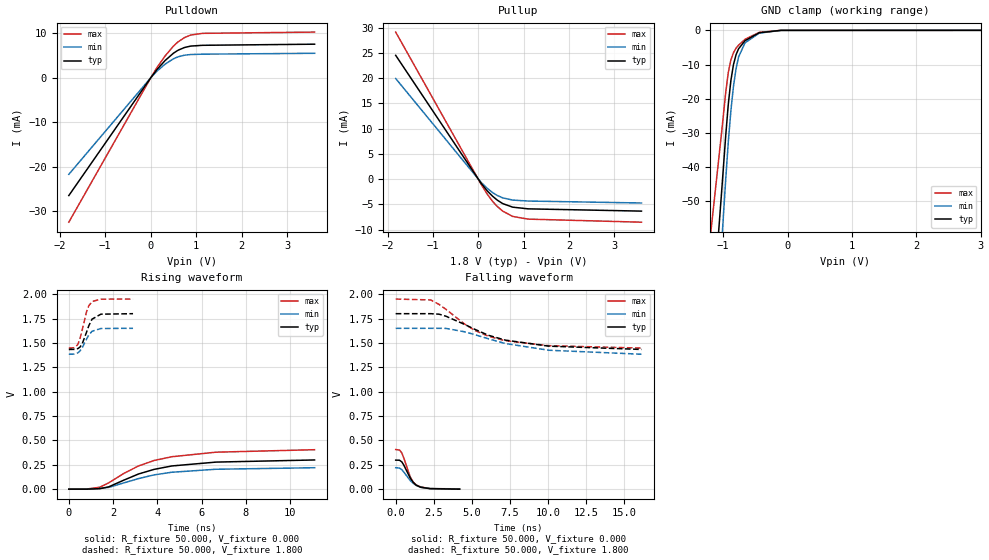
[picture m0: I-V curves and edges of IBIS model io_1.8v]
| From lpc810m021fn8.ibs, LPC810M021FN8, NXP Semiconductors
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[Model]   io_1.8v
Model_type I/O
Vinl=5.600E-01
Vinh=1.260E+00
Vref=0.000E+00
Rref=1.000E+06
Cref=2.000E-11
Vmeas=9.000E-01
C_comp   6.740E-13   6.620E-13   6.860E-13
[Voltage Range]   1.800E+00   1.650E+00   1.950E+00
[POWER Clamp Reference]   1.800E+00   1.650E+00   1.950E+00
[GND Clamp Reference]   0.000E+00   0.000E+00   0.000E+00
[Pullup Reference]   1.800E+00   1.650E+00   1.950E+00
[Pulldown Reference]   0.000E+00   0.000E+00   0.000E+00
[Temperature Range]   25   85   -40
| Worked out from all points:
|   slope of the pulldown table from 0 to 0.27 V, typ, clamps not added: 80.1 ohm
|   slope of the pullup table from 0 to 0.27 V, typ, clamps not added: 90.2 ohm
|   GND clamp passes 1 mA (typ) near -0.48 V on its own axis
|   rising waveform, R_fixture 50.000, V_fixture 0.000: 20-80 % time 2.52ns typ, 2.55ns min, 2.51ns max; typ from 0 V to 0.3 V
|   falling waveform, R_fixture 50.000, V_fixture 0.000: 20-80 % time 651ps typ, 759ps min, 578ps max; typ from 0.298 V to 0 V
|   rising waveform, R_fixture 50.000, V_fixture 1.800: 20-80 % time 362ps typ, 383ps min, 333ps max; typ from 1.43 V to 1.8 V
|   falling waveform, R_fixture 50.000, V_fixture 1.800: 20-80 % time 3.86ns typ, 4.4ns min, 3.27ns max; typ from 1.8 V to 1.43 V
[GND Clamp]
-1.8V     -242.4mA   -287.8mA   -165mA
-1.02V    -46.29mA   -61.32mA   -29.16mA
-960mV    -30.77mA   -43.57mA   -18.16mA
-920mV    -21.6mA    -32.63mA   -12.29mA
-880mV    -14.71mA   -23.53mA   -8.671mA
-840mV    -10.06mA   -16.42mA   -6.556mA
-800mV    -7.156mA   -11.27mA   -5.232mA
-760mV    -5.384mA   -7.778mA   -4.336mA
-660mV    -3.035mA   -3.64mA    -2.632mA
-440mV    -704.5uA   -820uA     -592.1uA
-100mV    -9.589uA   -9.536uA   -9.136uA
3.6V      0A         0A         0A
[POWER Clamp]
-1.8V     0A         0A         0A
3.6V      0A         0A         0A
[Pullup]
-1.82V    24.51mA    19.92mA    29.11mA
60mV      -766.2uA   -617.8uA   -963.6uA
200mV     -2.341mA   -1.823mA   -2.986mA
320mV     -3.405mA   -2.678mA   -4.431mA
420mV     -4.154mA   -3.232mA   -5.407mA
540mV     -4.841mA   -3.705mA   -6.323mA
760mV     -5.544mA   -4.145mA   -7.381mA
1.1V      -5.879mA   -4.334mA   -7.913mA
3.6V      -6.329mA   -4.721mA   -8.521mA
[Pulldown]
-1.8V     -26.43mA   -21.67mA   -32.41mA
0V        0A         0A         0A
140mV     1.894mA    1.523mA    2.358mA
320mV     3.92mA     3.098mA    4.957mA
500mV     5.527mA    4.271mA    7.12mA
600mV     6.186mA    4.71mA     8.066mA
740mV     6.795mA    5.068mA    9.018mA
880mV     7.12mA     5.225mA    9.607mA
1.14V     7.295mA    5.305mA    9.978mA
3.6V      7.545mA    5.5mA      10.26mA
[Rising Waveform]
R_fixture = 50.000
V_fixture = 0.000
V_fixture_min = 0.000
V_fixture_max = 0.000
|  time   V(typ)   V(min)   V(max)
0s        0V         0V         0V
800ps     0V         168.8uV    872.5uV
1.4ns     5.264mV    7.282mV    19.99mV
1.8ns     23.48mV    18.16mV    64.63mV
2.5ns     94.07mV    65.37mV    163.5mV
3.15ns    155.8mV    108.5mV    238.2mV
3.85ns    202.9mV    146.5mV    294.1mV
4.65ns    238mV      173.5mV    332.7mV
6.65ns    277.7mV    204.3mV    379.4mV
11.1ns    299.6mV    220mV      404.8mV
[Falling Waveform]
R_fixture = 50.000
V_fixture = 0.000
V_fixture_min = 0.000
V_fixture_max = 0.000
|  time   V(typ)   V(min)   V(max)
0s        297.7mV    220mV      406.4mV
250ps     296.7mV    215.6mV    401.2mV
400ps     280mV      199.9mV    372.6mV
550ps     241.9mV    171.9mV    311.6mV
950ps     114.7mV    88.71mV    127.8mV
1.15ns    70.2mV     59.92mV    71.95mV
1.35ns    40.18mV    37.95mV    42.5mV
1.65ns    19.07mV    18.68mV    23mV
2.25ns    5.265mV    6.356mV    5.01mV
4.2ns     -267.3uV   0V         3.238mV
[Rising Waveform]
R_fixture = 50.000
V_fixture = 1.800
V_fixture_min = 1.650
V_fixture_max = 1.950
|  time   V(typ)   V(min)   V(max)
0s        1.433V     1.384V     1.447V
250ps     1.434V     1.386V     1.451V
400ps     1.441V     1.397V     1.482V
500ps     1.456V     1.417V     1.539V
600ps     1.488V     1.449V     1.628V
800ps     1.61V      1.539V     1.82V
900ps     1.675V     1.58V      1.88V
1.05ns    1.744V     1.62V      1.925V
1.45ns    1.795V     1.648V     1.949V
2.9ns     1.8V       1.65V      1.95V
[Falling Waveform]
R_fixture = 50.000
V_fixture = 1.800
V_fixture_min = 1.650
V_fixture_max = 1.950
|  time   V(typ)   V(min)   V(max)
0s        1.8V       1.65V      1.95V
2.3ns     1.8V       1.65V      1.941V
2.85ns    1.795V     1.65V      1.895V
3.3ns     1.774V     1.649V     1.845V
4.5ns     1.692V     1.615V     1.697V
5.15ns    1.643V     1.587V     1.632V
6.1ns     1.578V     1.542V     1.568V
7.2ns     1.529V     1.494V     1.523V
10.05ns   1.467V     1.425V     1.472V
16.15ns   1.433V     1.384V     1.447V
[Ramp]
dV/dt_r   1.7879E-01/2.5172E-09   1.3259E-01/2.5500E-09   2.4189E-01/2.5051E-09
dV/dt_f   2.2008E-01/3.8545E-09   1.5972E-01/4.3945E-09   3.0181E-01/3.2617E-09
R_load = 50
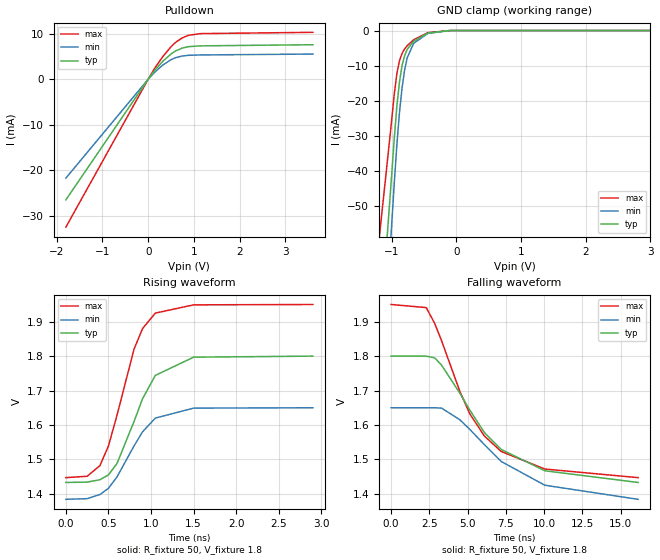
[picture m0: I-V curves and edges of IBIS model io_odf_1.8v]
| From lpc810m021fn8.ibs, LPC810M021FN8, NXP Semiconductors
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[Model]   io_odf_1.8v
Model_type I/O_open_drain
Vinl=5.600E-01
Vinh=1.260E+00
Vref=1.800E+00
Rref=1.000E+03
Cref=2.000E-11
Vmeas=9.000E-01
C_comp   6.740E-13   6.620E-13   6.860E-13
[Voltage Range]   1.800E+00   1.650E+00   1.950E+00
[POWER Clamp Reference]   1.800E+00   1.650E+00   1.950E+00
[GND Clamp Reference]   0.000E+00   0.000E+00   0.000E+00
[Pullup Reference]   1.800E+00   1.650E+00   1.950E+00
[Pulldown Reference]   0.000E+00   0.000E+00   0.000E+00
[Temperature Range]   25   85   -40
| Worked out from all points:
|   slope of the pulldown table from 0 to 0.27 V, typ, clamps not added: 80.1 ohm
|   GND clamp passes 1 mA (typ) near -0.48 V on its own axis
|   rising waveform, R_fixture 50, V_fixture 1.8: 20-80 % time 363ps typ, 384ps min, 333ps max; typ from 1.43 V to 1.8 V
|   falling waveform, R_fixture 50, V_fixture 1.8: 20-80 % time 3.86ns typ, 4.4ns min, 3.27ns max; typ from 1.8 V to 1.43 V
[GND Clamp]
-1.8V     -242.4mA   -287.8mA   -165mA
-1.02V    -46.29mA   -61.32mA   -29.16mA
-960mV    -30.77mA   -43.57mA   -18.16mA
-920mV    -21.6mA    -32.63mA   -12.29mA
-880mV    -14.71mA   -23.53mA   -8.671mA
-840mV    -10.06mA   -16.42mA   -6.556mA
-800mV    -7.156mA   -11.27mA   -5.232mA
-760mV    -5.384mA   -7.778mA   -4.336mA
-660mV    -3.035mA   -3.64mA    -2.632mA
-440mV    -704.5uA   -820uA     -592.1uA
-100mV    -9.589uA   -9.536uA   -9.136uA
3.6V      0A         0A         0A
[Pulldown]
-1.8V     -26.43mA   -21.67mA   -32.41mA
0V        0A         0A         0A
140mV     1.894mA    1.523mA    2.358mA
320mV     3.92mA     3.098mA    4.957mA
500mV     5.527mA    4.271mA    7.12mA
600mV     6.186mA    4.71mA     8.066mA
740mV     6.795mA    5.068mA    9.018mA
880mV     7.12mA     5.225mA    9.607mA
1.14V     7.295mA    5.305mA    9.978mA
3.6V      7.545mA    5.5mA      10.26mA
[Rising Waveform]
R_fixture = 50
V_fixture = 1.8
V_fixture_min = 1.65
V_fixture_max = 1.95
0s        1.433V     1.384V     1.447V
250ps     1.434V     1.386V     1.451V
400ps     1.441V     1.398V     1.482V
500ps     1.455V     1.416V     1.539V
600ps     1.488V     1.449V     1.628V
800ps     1.61V      1.539V     1.82V
900ps     1.676V     1.58V      1.88V
1.05ns    1.744V     1.62V      1.925V
1.5ns     1.797V     1.649V     1.949V
2.9ns     1.8V       1.65V      1.95V
[Falling Waveform]
R_fixture = 50
V_fixture = 1.8
V_fixture_min = 1.65
V_fixture_max = 1.95
0s        1.8V       1.65V      1.95V
2.3ns     1.8V       1.65V      1.941V
2.85ns    1.795V     1.65V      1.895V
3.3ns     1.774V     1.649V     1.845V
4.5ns     1.692V     1.615V     1.697V
5.15ns    1.643V     1.587V     1.632V
6.1ns     1.578V     1.543V     1.568V
7.2ns     1.529V     1.494V     1.523V
10.05ns   1.467V     1.425V     1.472V
16.15ns   1.433V     1.384V     1.447V
[Ramp]
dV/dt_r   2.2008E-01/3.6140E-10   1.5972E-01/3.8230E-10   3.0181E-01/3.3140E-10
dV/dt_f   2.2008E-01/3.8545E-09   1.5972E-01/4.3945E-09   3.0181E-01/3.2617E-09
R_load = 50
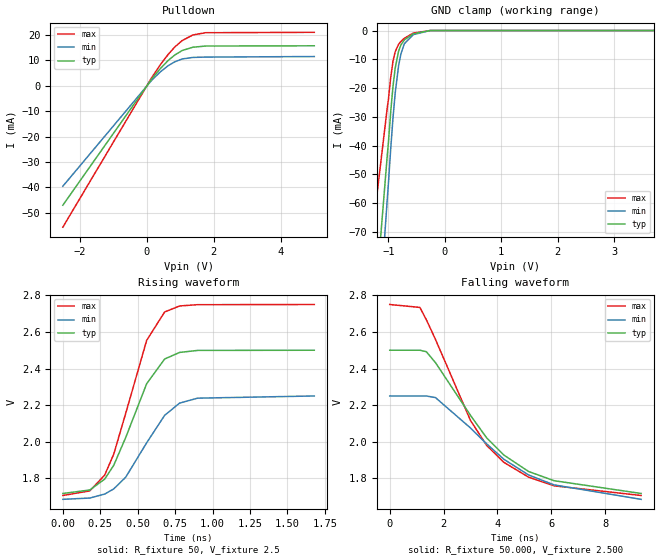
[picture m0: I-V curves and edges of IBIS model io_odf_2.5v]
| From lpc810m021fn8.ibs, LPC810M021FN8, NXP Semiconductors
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[Model]   io_odf_2.5v
Model_type I/O_open_drain
Vinl=7.500E-01
Vinh=1.750E+00
Vref=2.500E+00
Rref=1.000E+03
Cref=2.000E-11
Vmeas=1.250E+00
C_comp   6.740E-13   6.620E-13   6.860E-13
[Voltage Range]   2.500E+00   2.250E+00   2.750E+00
[POWER Clamp Reference]   2.500E+00   2.250E+00   2.750E+00
[GND Clamp Reference]   0.000E+00   0.000E+00   0.000E+00
[Pullup Reference]   2.500E+00   2.250E+00   2.750E+00
[Pulldown Reference]   0.000E+00   0.000E+00   0.000E+00
[Temperature Range]   25   85   -40
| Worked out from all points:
|   slope of the pulldown table from 0 to 0.375 V, typ, clamps not added: 59.6 ohm
|   GND clamp passes 1 mA (typ) near -0.54 V on its own axis
|   rising waveform, R_fixture 50, V_fixture 2.5: 20-80 % time 235ps typ, 260ps min, 222ps max; typ from 1.72 V to 2.5 V
|   falling waveform, R_fixture 50.000, V_fixture 2.500: 20-80 % time 2.6ns typ, 2.89ns min, 2.27ns max; typ from 2.5 V to 1.72 V
[GND Clamp]
-2.5V     -401.2mA   -475.8mA   -271.1mA
-1.02V    -43.24mA   -58.4mA    -26.73mA
-1V       -38.82mA   -53.05mA   -23.92mA
-960mV    -28.29mA   -41.17mA   -16.3mA
-920mV    -19.52mA   -30.53mA   -10.75mA
-880mV    -13.03mA   -21.7mA    -7.353mA
-820mV    -7.166mA   -12.22mA   -4.778mA
-780mV    -5.051mA   -8.202mA   -3.828mA
-720mV    -3.296mA   -4.639mA   -2.72mA
-560mV    -1.152mA   -1.423mA   -887.5uA
-260mV    0A         0A         0A
5V        0A         0A         0A
[Pulldown]
-2.5V     -47.05mA   -39.57mA   -55.7mA
160mV     2.855mA    2.346mA    3.443mA
420mV     6.978mA    5.638mA    8.533mA
640mV     9.968mA    7.915mA    12.35mA
840mV     12.16mA    9.473mA    15.31mA
1.06V     13.92mA    10.58mA    17.85mA
1.38V     15.21mA    11.19mA    20.05mA
1.76V     15.68mA    11.32mA    20.93mA
5V        15.77mA    11.54mA    21.08mA
[Rising Waveform]
R_fixture = 50
V_fixture = 2.5
V_fixture_min = 2.25
V_fixture_max = 2.75
0s        1.717V     1.685V     1.706V
180ps     1.736V     1.692V     1.731V
280ps     1.796V     1.714V     1.818V
340ps     1.871V     1.742V     1.932V
420ps     2.023V     1.806V     2.155V
560ps     2.317V     1.994V     2.554V
680ps     2.452V     2.144V     2.709V
780ps     2.488V     2.211V     2.742V
900ps     2.499V     2.238V     2.749V
1.68ns    2.5V       2.25V      2.75V
[Falling Waveform]
R_fixture = 50.000
V_fixture = 2.500
V_fixture_min = 2.250
V_fixture_max = 2.750
|  time   V(typ)   V(min)   V(max)
0s        2.5V       2.25V      2.75V
1.12ns    2.5V       2.25V      2.734V
1.36ns    2.492V     2.25V      2.667V
1.7ns     2.432V     2.241V     2.559V
3ns       2.144V     2.075V     2.116V
3.6ns     2.021V     1.988V     1.98V
4.24ns    1.927V     1.904V     1.887V
5.16ns    1.837V     1.818V     1.806V
6.1ns     1.787V     1.764V     1.759V
9.34ns    1.717V     1.685V     1.706V
[Ramp]
dV/dt_r   4.7003E-01/2.3430E-10   3.3892E-01/2.5980E-10   6.2651E-01/2.2120E-10
dV/dt_f   4.7003E-01/2.5911E-09   3.3892E-01/2.8894E-09   6.2651E-01/2.2591E-09
R_load = 50
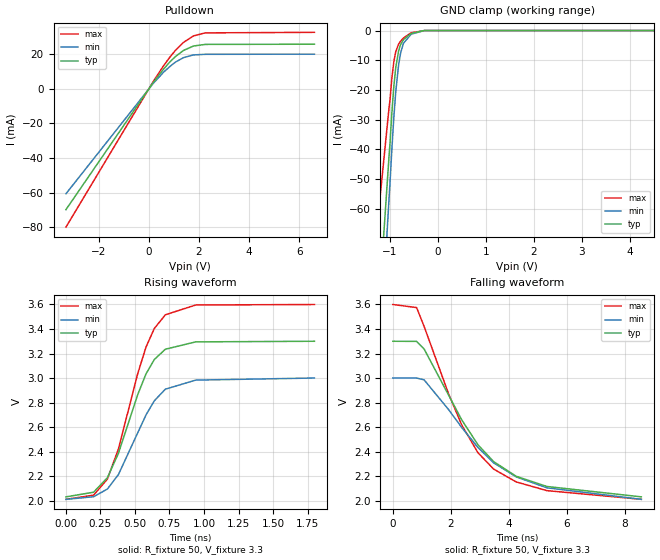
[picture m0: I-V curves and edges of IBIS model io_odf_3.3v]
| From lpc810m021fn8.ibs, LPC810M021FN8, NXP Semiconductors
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[Model]   io_odf_3.3v
Model_type I/O_open_drain
Vinl=9.900E-01
Vinh=2.310E+00
Vref=3.300E+00
Rref=1.000E+03
Cref=2.000E-11
Vmeas=1.650E+00
C_comp   6.740E-13   6.620E-13   6.860E-13
[Voltage Range]   3.300E+00   3.000E+00   3.600E+00
[POWER Clamp Reference]   3.300E+00   3.000E+00   3.600E+00
[GND Clamp Reference]   0.000E+00   0.000E+00   0.000E+00
[Pullup Reference]   3.300E+00   3.000E+00   3.600E+00
[Pulldown Reference]   0.000E+00   0.000E+00   0.000E+00
[Temperature Range]   25   85   -40
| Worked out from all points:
|   slope of the pulldown table from 0 to 0.495 V, typ, clamps not added: 51 ohm
|   GND clamp passes 1 mA (typ) near -0.56 V on its own axis
|   rising waveform, R_fixture 50, V_fixture 3.3: 20-80 % time 241ps typ, 255ps min, 236ps max; typ from 2.03 V to 3.3 V
|   falling waveform, R_fixture 50, V_fixture 3.3: 20-80 % time 2.13ns typ, 2.41ns min, 1.86ns max; typ from 3.3 V to 2.03 V
[GND Clamp]
-3.3V     -588.5mA   -689.5mA   -393.5mA
-1.02V    -42.37mA   -56.7mA    -26.07mA
-1V       -37.98mA   -51.44mA   -23.34mA
-960mV    -27.56mA   -39.74mA   -15.89mA
-920mV    -18.87mA   -29.27mA   -10.48mA
-880mV    -12.49mA   -20.67mA   -7.138mA
-820mV    -6.819mA   -11.51mA   -4.563mA
-780mV    -4.759mA   -7.653mA   -3.619mA
-720mV    -3.08mA    -4.31mA    -2.548mA
-560mV    -996.8uA   -1.246mA   -753.3uA
-280mV    0A         0A         0A
6.6V      0A         0A         0A
[Pulldown]
-3.3V     -69.88mA   -60.71mA   -80.02mA
180mV     3.701mA    3.169mA    4.292mA
580mV     11.24mA    9.48mA     13.18mA
840mV     15.57mA    12.9mA     18.32mA
1.06V     18.64mA    15.43mA    22.24mA
1.38V     22.17mA    18.03mA    26.83mA
1.78V     24.76mA    19.6mA     30.59mA
2.24V     25.69mA    19.96mA    32.36mA
6.6V      25.81mA    20.05mA    32.68mA
[Rising Waveform]
R_fixture = 50
V_fixture = 3.3
V_fixture_min = 3
V_fixture_max = 3.6
0s        2.03V      2.01V      2.01V
200ps     2.068V     2.031V     2.044V
300ps     2.186V     2.094V     2.175V
380ps     2.385V     2.212V     2.421V
520ps     2.865V     2.553V     3.036V
580ps     3.034V     2.699V     3.253V
640ps     3.151V     2.814V     3.404V
720ps     3.235V     2.909V     3.516V
940ps     3.295V     2.983V     3.596V
1.8ns     3.3V       3V         3.6V
[Falling Waveform]
R_fixture = 50
V_fixture = 3.3
V_fixture_min = 3
V_fixture_max = 3.6
0s        3.3V       3V         3.6V
820ps     3.299V     3V         3.575V
1.08ns    3.237V     2.985V     3.421V
1.92ns    2.863V     2.744V     2.874V
2.38ns    2.658V     2.596V     2.616V
2.94ns    2.455V     2.433V     2.39V
3.48ns    2.318V     2.308V     2.257V
4.26ns    2.198V     2.193V     2.152V
5.32ns    2.115V     2.104V     2.081V
8.58ns    2.03V      2.01V      2.01V
[Ramp]
dV/dt_r   7.6177E-01/2.4080E-10   5.9414E-01/2.5490E-10   9.5373E-01/2.3520E-10
dV/dt_f   7.6177E-01/2.1256E-09   5.9414E-01/2.3999E-09   9.5373E-01/1.8626E-09
R_load = 50
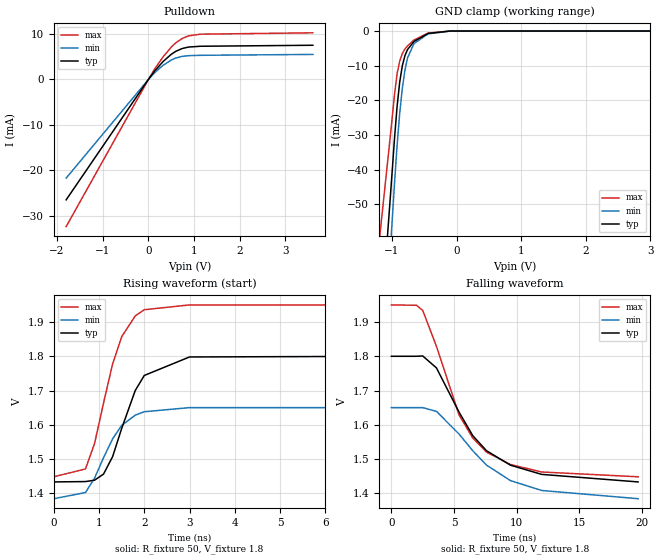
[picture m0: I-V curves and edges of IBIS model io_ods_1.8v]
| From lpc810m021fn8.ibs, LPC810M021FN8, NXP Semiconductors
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[Model]   io_ods_1.8v
Model_type I/O_open_drain
Vinl=5.400E-01
Vinh=1.260E+00
Vref=1.8000E+00
Rref=1.0000E+03
Cref=2.000E-11
Vmeas=9.000E-01
C_comp   8.440E-13   8.280E-13   8.600E-13
[Voltage Range]   1.800E+00   1.650E+00   1.950E+00
[POWER Clamp Reference]   1.800E+00   1.650E+00   1.950E+00
[GND Clamp Reference]   0.000E+00   0.000E+00   0.000E+00
[Pullup Reference]   1.800E+00   1.650E+00   1.950E+00
[Pulldown Reference]   0.000E+00   0.000E+00   0.000E+00
[Temperature Range]   25   85   -40
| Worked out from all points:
|   slope of the pulldown table from 0 to 0.27 V, typ, clamps not added: 80.1 ohm
|   GND clamp passes 1 mA (typ) near -0.49 V on its own axis
|   rising waveform, R_fixture 50, V_fixture 1.8: 20-80 % time 612ps typ, 623ps min, 572ps max; typ from 1.43 V to 1.8 V
|   falling waveform, R_fixture 50, V_fixture 1.8: 20-80 % time 4.03ns typ, 4.68ns min, 3.37ns max; typ from 1.8 V to 1.43 V
[GND Clamp]
-1.8V     -244.7mA   -289.3mA   -167mA
-1.02V    -46.52mA   -61.63mA   -29.35mA
-960mV    -30.82mA   -43.78mA   -18.18mA
-920mV    -21.59mA   -32.78mA   -12.28mA
-880mV    -14.7mA    -23.66mA   -8.632mA
-840mV    -10.06mA   -16.55mA   -6.501mA
-800mV    -7.146mA   -11.36mA   -5.216mA
-760mV    -5.376mA   -7.82mA    -4.319mA
-660mV    -3.02mA    -3.637mA   -2.604mA
-440mV    -697.2uA   -814.9uA   -584.6uA
-100mV    -9.428uA   -9.367uA   -9.062uA
3.6V      0A         0A         0A
[Pulldown]
-1.8V     -26.45mA   -21.68mA   -32.33mA
0V        0A         0A         0A
140mV     1.894mA    1.524mA    2.352mA
320mV     3.921mA    3.1mA      4.945mA
500mV     5.53mA     4.273mA    7.104mA
600mV     6.19mA     4.713mA    8.047mA
740mV     6.8mA      5.071mA    8.997mA
880mV     7.124mA    5.228mA    9.584mA
1.14V     7.298mA    5.309mA    9.953mA
3.6V      7.517mA    5.502mA    10.25mA
[Rising Waveform]
R_fixture = 50
V_fixture = 1.8
V_fixture_min = 1.65
V_fixture_max = 1.95
0s        1.433V     1.384V     1.448V
700ps     1.434V     1.402V     1.471V
900ps     1.438V     1.444V     1.545V
1.1ns     1.456V     1.504V     1.664V
1.3ns     1.507V     1.559V     1.778V
1.5ns     1.589V     1.598V     1.857V
1.8ns     1.7V       1.628V     1.918V
2ns       1.744V     1.638V     1.936V
3ns       1.798V     1.65V      1.95V
7.7ns     1.8V       1.65V      1.95V
[Falling Waveform]
R_fixture = 50
V_fixture = 1.8
V_fixture_min = 1.65
V_fixture_max = 1.95
0s        1.8V       1.65V      1.95V
2ns       1.8V       1.65V      1.949V
2.5ns     1.801V     1.65V      1.934V
3.6ns     1.766V     1.639V     1.829V
5.4ns     1.637V     1.573V     1.629V
6.5ns     1.568V     1.524V     1.561V
7.6ns     1.524V     1.482V     1.52V
9.5ns     1.482V     1.437V     1.484V
12ns      1.455V     1.408V     1.462V
19.7ns    1.433V     1.384V     1.448V
[Ramp]
dV/dt_r   2.2020E-01/6.1100E-10   1.5981E-01/6.1960E-10   3.0112E-01/5.6930E-10
dV/dt_f   2.2020E-01/4.0258E-09   1.5981E-01/4.6723E-09   3.0112E-01/3.3613E-09
R_load = 50
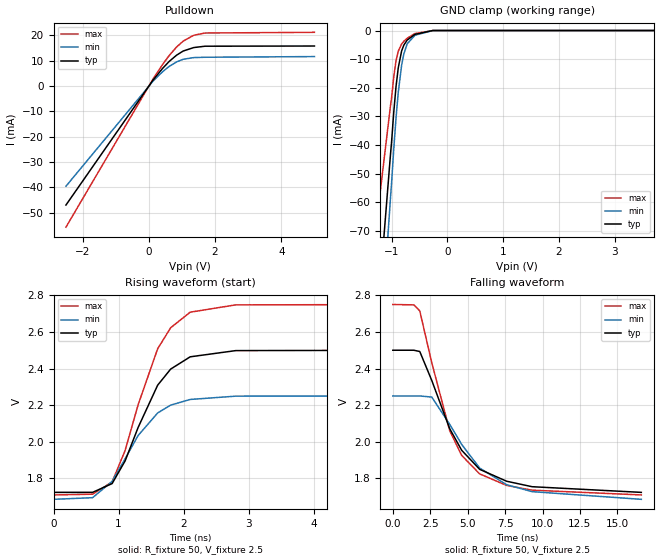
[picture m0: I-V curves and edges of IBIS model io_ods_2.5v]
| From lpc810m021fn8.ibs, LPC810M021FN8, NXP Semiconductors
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[Model]   io_ods_2.5v
Model_type I/O_open_drain
Vinl=7.500E-01
Vinh=1.750E+00
Vref=2.5000E+00
Rref=1.0000E+03
Cref=2.000E-11
Vmeas=1.250E+00
C_comp   8.440E-13   8.280E-13   8.600E-13
[Voltage Range]   2.500E+00   2.250E+00   2.750E+00
[POWER Clamp Reference]   2.500E+00   2.250E+00   2.750E+00
[GND Clamp Reference]   0.000E+00   0.000E+00   0.000E+00
[Pullup Reference]   2.500E+00   2.250E+00   2.750E+00
[Pulldown Reference]   0.000E+00   0.000E+00   0.000E+00
[Temperature Range]   25   85   -40
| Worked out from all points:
|   slope of the pulldown table from 0 to 0.375 V, typ, clamps not added: 59.7 ohm
|   GND clamp passes 1 mA (typ) near -0.54 V on its own axis
|   rising waveform, R_fixture 50, V_fixture 2.5: 20-80 % time 594ps typ, 611ps min, 587ps max; typ from 1.72 V to 2.5 V
|   falling waveform, R_fixture 50, V_fixture 2.5: 20-80 % time 2.81ns typ, 3.33ns min, 2.37ns max; typ from 2.5 V to 1.72 V
[GND Clamp]
-2.5V     -404.4mA   -481mA     -268.3mA
-1.02V    -43.49mA   -58.74mA   -26.39mA
-1V       -39.04mA   -53.33mA   -23.63mA
-960mV    -28.39mA   -41.3mA    -16.04mA
-920mV    -19.57mA   -30.54mA   -10.58mA
-880mV    -13.05mA   -21.66mA   -7.23mA
-820mV    -7.167mA   -12.19mA   -4.716mA
-780mV    -5.099mA   -8.191mA   -3.748mA
-720mV    -3.33mA    -4.644mA   -2.706mA
-580mV    -1.348mA   -1.652mA   -1.054mA
-260mV    0A         0A         0A
5V        0A         0A         0A
[Pulldown]
-2.5V     -46.95mA   -39.54mA   -55.67mA
140mV     2.506mA    2.066mA    3.025mA
420mV     6.967mA    5.639mA    8.535mA
620mV     9.719mA    7.744mA    12.05mA
840mV     12.14mA    9.477mA    15.36mA
1.04V     13.78mA    10.52mA    17.7mA
1.36V     15.14mA    11.18mA    19.99mA
1.7V      15.67mA    11.31mA    20.87mA
5V        15.74mA    11.58mA    21.14mA
[Rising Waveform]
R_fixture = 50
V_fixture = 2.5
V_fixture_min = 2.25
V_fixture_max = 2.75
0s        1.723V     1.685V     1.709V
600ps     1.723V     1.694V     1.713V
900ps     1.771V     1.783V     1.78V
1.1ns     1.895V     1.907V     1.952V
1.3ns     2.078V     2.034V     2.202V
1.6ns     2.309V     2.157V     2.508V
1.8ns     2.397V     2.2V       2.623V
2.1ns     2.464V     2.231V     2.708V
2.8ns     2.498V     2.249V     2.748V
5.9ns     2.5V       2.25V      2.75V
[Falling Waveform]
R_fixture = 50
V_fixture = 2.5
V_fixture_min = 2.25
V_fixture_max = 2.75
0s        2.5V       2.25V      2.75V
1.4ns     2.5V       2.25V      2.748V
1.8ns     2.493V     2.25V      2.715V
2.6ns     2.335V     2.244V     2.432V
3.8ns     2.071V     2.095V     2.06V
4.6ns     1.953V     1.985V     1.925V
5.8ns     1.849V     1.856V     1.824V
7.6ns     1.784V     1.765V     1.761V
9.3ns     1.754V     1.727V     1.735V
16.6ns    1.723V     1.685V     1.709V
[Ramp]
dV/dt_r   4.6607E-01/5.8910E-10   3.3898E-01/6.0560E-10   6.2439E-01/5.8070E-10
dV/dt_f   4.6607E-01/2.8065E-09   3.3898E-01/3.2420E-09   6.2439E-01/2.3520E-09
R_load = 50
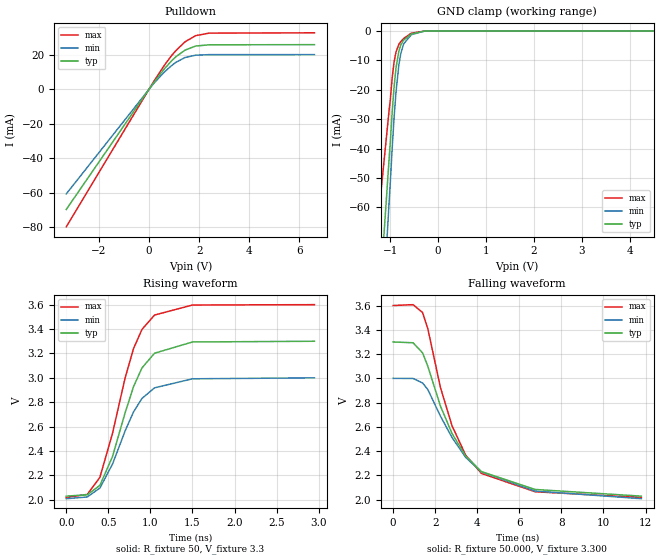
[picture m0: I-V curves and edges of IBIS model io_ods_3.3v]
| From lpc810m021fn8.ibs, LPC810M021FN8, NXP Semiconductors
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[Model]   io_ods_3.3v
Model_type I/O_open_drain
Vinl=9.900E-01
Vinh=2.310E+00
Vref=3.300E+00
Rref=1.000E+03
Cref=2.000E-11
Vmeas=1.650E+00
C_comp   8.440E-13   8.280E-13   8.600E-13
[Voltage Range]   3.300E+00   3.000E+00   3.600E+00
[POWER Clamp Reference]   3.300E+00   3.000E+00   3.600E+00
[GND Clamp Reference]   0.000E+00   0.000E+00   0.000E+00
[Pullup Reference]   3.300E+00   3.000E+00   3.600E+00
[Pulldown Reference]   0.000E+00   0.000E+00   0.000E+00
[Temperature Range]   25   85   -40
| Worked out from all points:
|   slope of the pulldown table from 0 to 0.495 V, typ, clamps not added: 51.2 ohm
|   GND clamp passes 1 mA (typ) near -0.56 V on its own axis
|   rising waveform, R_fixture 50, V_fixture 3.3: 20-80 % time 360ps typ, 375ps min, 352ps max; typ from 2.03 V to 3.3 V
|   falling waveform, R_fixture 50.000, V_fixture 3.300: 20-80 % time 2.09ns typ, 2.46ns min, 1.77ns max; typ from 3.3 V to 2.03 V
[GND Clamp]
-3.3V     -590.4mA   -698mA     -398.8mA
-1.02V    -42.46mA   -57.07mA   -26.24mA
-1V       -38.06mA   -51.76mA   -23.49mA
-960mV    -27.61mA   -39.88mA   -15.89mA
-920mV    -18.88mA   -29.31mA   -10.45mA
-880mV    -12.49mA   -20.65mA   -7.085mA
-820mV    -6.778mA   -11.45mA   -4.527mA
-780mV    -4.748mA   -7.624mA   -3.589mA
-720mV    -3.081mA   -4.344mA   -2.525mA
-560mV    -993.4uA   -1.241mA   -739uA
-280mV    0A         0A         0A
6.6V      0A         0A         0A
[Pulldown]
-3.3V     -69.61mA   -60.63mA   -79.67mA
160mV     3.297mA    2.832mA    3.818mA
600mV     11.55mA    9.76mA     13.55mA
900mV     16.39mA    13.61mA    19.41mA
1.08V     18.87mA    15.6mA     22.43mA
1.44V     22.62mA    18.34mA    27.44mA
1.86V     24.96mA    19.68mA    30.98mA
2.4V      25.7mA     20mA       32.46mA
6.6V      25.77mA    20.01mA    32.62mA
[Rising Waveform]
R_fixture = 50
V_fixture = 3.3
V_fixture_min = 3
V_fixture_max = 3.6
0s        2.03V      2.009V     2.019V
250ps     2.041V     2.023V     2.044V
400ps     2.118V     2.096V     2.184V
550ps     2.355V     2.293V     2.545V
700ps     2.714V     2.565V     3V
800ps     2.928V     2.721V     3.24V
900ps     3.081V     2.831V     3.397V
1.05ns    3.202V     2.918V     3.515V
1.5ns     3.294V     2.992V     3.597V
2.95ns    3.3V       3V         3.6V
[Falling Waveform]
R_fixture = 50.000
V_fixture = 3.300
V_fixture_min = 3.000
V_fixture_max = 3.600
|  time   V(typ)   V(min)   V(max)
0s        3.3V       3V         3.6V
950ps     3.293V     2.999V     3.607V
1.4ns     3.21V      2.962V     3.542V
1.65ns    3.1V       2.908V     3.409V
2.25ns    2.772V     2.689V     2.925V
2.8ns     2.546V     2.513V     2.61V
3.45ns    2.36V      2.349V     2.367V
4.2ns     2.232V     2.229V     2.217V
6.75ns    2.085V     2.072V     2.066V
11.8ns    2.03V      2.009V     2.019V
[Ramp]
dV/dt_r   7.6204E-01/3.5770E-10   5.9483E-01/3.7310E-11   9.4867E-01/3.4960E-10
dV/dt_f   7.6204E-01/2.0907E-09   5.9483E-01/2.4504E-09   9.4867E-01/1.7686E-09
R_load = 50
